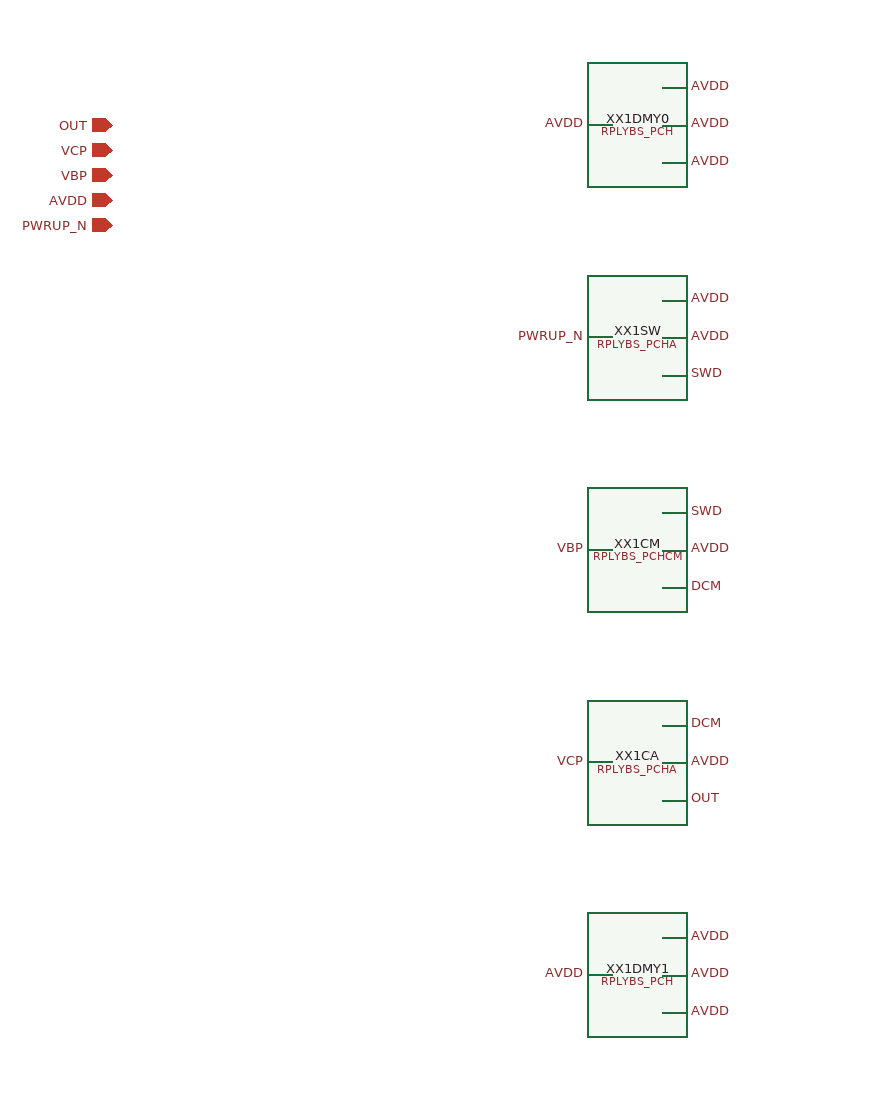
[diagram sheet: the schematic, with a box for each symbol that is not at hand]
v {xschem version=3.0.0 file_version=1.2 }
G {}
K {}
V {}
S {}
E {}
C {devices/iopin.sym} 0 0 0 0{name=p0 lab=OUT}
C {devices/iopin.sym} 0 20 0 0{name=p1 lab=VCP}
C {devices/iopin.sym} 0 40 0 0{name=p2 lab=VBP}
C {devices/iopin.sym} 0 60 0 0{name=p3 lab=AVDD}
C {devices/iopin.sym} 0 80 0 0{name=p4 lab=PWRUP_N}
C {RPLY_BIAS_SKY130NM/RPLYBS_PCH.sym} 400 0 0 0 {name=XX1DMY0}
N 460.0 30.0 440.0 30.0{lab=AVDD}
C {devices/lab_pin.sym} 460.0 30.0 2 0  {name=l0 sig_type=std_logic lab=AVDD }
N 380.0 0.0 400.0 0.0{lab=AVDD}
C {devices/lab_pin.sym} 380.0 0.0 0 0  {name=l1 sig_type=std_logic lab=AVDD }
N 460.0 -30.0 440.0 -30.0{lab=AVDD}
C {devices/lab_pin.sym} 460.0 -30.0 2 0  {name=l2 sig_type=std_logic lab=AVDD }
N 460.0 0.0 440.0 0.0{lab=AVDD}
C {devices/lab_pin.sym} 460.0 0.0 2 0  {name=l3 sig_type=std_logic lab=AVDD }
C {RPLY_BIAS_SKY130NM/RPLYBS_PCHA.sym} 400 170.0 0 0 {name=XX1SW}
N 460.0 200.0 440.0 200.0{lab=SWD}
C {devices/lab_pin.sym} 460.0 200.0 2 0  {name=l4 sig_type=std_logic lab=SWD }
N 380.0 170.0 400.0 170.0{lab=PWRUP_N}
C {devices/lab_pin.sym} 380.0 170.0 0 0  {name=l5 sig_type=std_logic lab=PWRUP_N }
N 460.0 140.0 440.0 140.0{lab=AVDD}
C {devices/lab_pin.sym} 460.0 140.0 2 0  {name=l6 sig_type=std_logic lab=AVDD }
N 460.0 170.0 440.0 170.0{lab=AVDD}
C {devices/lab_pin.sym} 460.0 170.0 2 0  {name=l7 sig_type=std_logic lab=AVDD }
C {RPLY_BIAS_SKY130NM/RPLYBS_PCHCM.sym} 400 340.0 0 0 {name=XX1CM}
N 460.0 370.0 440.0 370.0{lab=DCM}
C {devices/lab_pin.sym} 460.0 370.0 2 0  {name=l8 sig_type=std_logic lab=DCM }
N 380.0 340.0 400.0 340.0{lab=VBP}
C {devices/lab_pin.sym} 380.0 340.0 0 0  {name=l9 sig_type=std_logic lab=VBP }
N 460.0 310.0 440.0 310.0{lab=SWD}
C {devices/lab_pin.sym} 460.0 310.0 2 0  {name=l10 sig_type=std_logic lab=SWD }
N 460.0 340.0 440.0 340.0{lab=AVDD}
C {devices/lab_pin.sym} 460.0 340.0 2 0  {name=l11 sig_type=std_logic lab=AVDD }
C {RPLY_BIAS_SKY130NM/RPLYBS_PCHA.sym} 400 510.0 0 0 {name=XX1CA}
N 460.0 540.0 440.0 540.0{lab=OUT}
C {devices/lab_pin.sym} 460.0 540.0 2 0  {name=l12 sig_type=std_logic lab=OUT }
N 380.0 510.0 400.0 510.0{lab=VCP}
C {devices/lab_pin.sym} 380.0 510.0 0 0  {name=l13 sig_type=std_logic lab=VCP }
N 460.0 480.0 440.0 480.0{lab=DCM}
C {devices/lab_pin.sym} 460.0 480.0 2 0  {name=l14 sig_type=std_logic lab=DCM }
N 460.0 510.0 440.0 510.0{lab=AVDD}
C {devices/lab_pin.sym} 460.0 510.0 2 0  {name=l15 sig_type=std_logic lab=AVDD }
C {RPLY_BIAS_SKY130NM/RPLYBS_PCH.sym} 400 680.0 0 0 {name=XX1DMY1}
N 460.0 710.0 440.0 710.0{lab=AVDD}
C {devices/lab_pin.sym} 460.0 710.0 2 0  {name=l16 sig_type=std_logic lab=AVDD }
N 380.0 680.0 400.0 680.0{lab=AVDD}
C {devices/lab_pin.sym} 380.0 680.0 0 0  {name=l17 sig_type=std_logic lab=AVDD }
N 460.0 650.0 440.0 650.0{lab=AVDD}
C {devices/lab_pin.sym} 460.0 650.0 2 0  {name=l18 sig_type=std_logic lab=AVDD }
N 460.0 680.0 440.0 680.0{lab=AVDD}
C {devices/lab_pin.sym} 460.0 680.0 2 0  {name=l19 sig_type=std_logic lab=AVDD }
